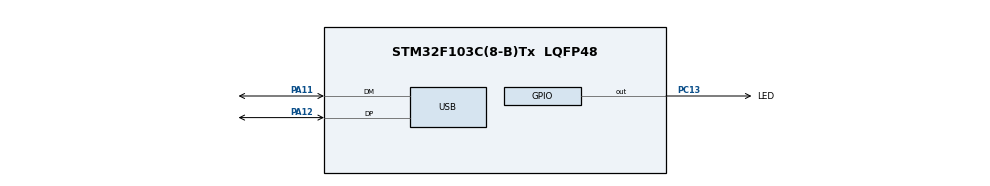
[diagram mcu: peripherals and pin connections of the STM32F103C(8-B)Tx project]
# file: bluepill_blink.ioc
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Mcu.Family=STM32F1
Mcu.Name=STM32F103C(8-B)Tx
Mcu.Package=LQFP48
NVIC.PriorityGroup=NVIC_PRIORITYGROUP_4
NVIC.USB_LP_CAN1_RX0_IRQn=true\:0\:0\:false\:false\:true
PA11.Mode=Device
PA11.Signal=USB_DM
PA12.Mode=Device
PA12.Signal=USB_DP
PA13.Mode=Serial_Wire
PA13.Signal=SYS_JTMS-SWDIO
PA14.Mode=Serial_Wire
PA14.Signal=SYS_JTCK-SWCLK
PC13-TAMPER-RTC.GPIO_Label=LED
PC13-TAMPER-RTC.Signal=GPIO_Output
PD0-OSC_IN.Mode=HSE-External-Oscillator
PD0-OSC_IN.Signal=RCC_OSC_IN
PD1-OSC_OUT.Mode=HSE-External-Oscillator
PD1-OSC_OUT.Signal=RCC_OSC_OUT
ProjectManager.HeapSize=0x200
ProjectManager.StackSize=0x400
ProjectManager.TargetToolchain=Makefile
RCC.AHBFreq_Value=48000000
RCC.APB1CLKDivider=RCC_HCLK_DIV2
RCC.APB1Freq_Value=24000000
RCC.APB1TimFreq_Value=48000000
RCC.APB2Freq_Value=48000000
RCC.APB2TimFreq_Value=48000000
RCC.HCLKFreq_Value=48000000
RCC.PLLMUL=RCC_PLL_MUL6
RCC.PLLSourceVirtual=RCC_PLLSOURCE_HSE
RCC.SYSCLKFreq_VALUE=48000000
RCC.SYSCLKSource=RCC_SYSCLKSOURCE_PLLCLK
RCC.USBFreq_Value=48000000
USB_DEVICE.CLASS_NAME_FS=CDC
USB_DEVICE.VirtualMode=Cdc
USB_DEVICE.VirtualModeFS=Cdc_FS
VP_USB_DEVICE_VS_USB_DEVICE_CDC_FS.Mode=CDC_FS
board=bluepill_blink

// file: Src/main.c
/**
  ******************************************************************************
  * File Name          : main.c
  * Description        : Main program body
  ******************************************************************************
  * This notice applies to any and all portions of this file
  * that are not between comment pairs USER CODE BEGIN and
  * USER CODE END. Other portions of this file, whether
  * inserted by the user or by software development tools
  * are owned by their respective copyright owners.
  *
  * Copyright (c) 2017 STMicroelectronics International N.V.
  * All rights reserved.
  *
  * Redistribution and use in source and binary forms, with or without
  * modification, are permitted, provided that the following conditions are met:
  *
  * 1. Redistribution of source code must retain the above copyright notice,
  *    this list of conditions and the following disclaimer.
  * 2. Redistributions in binary form must reproduce the above copyright notice,
  *    this list of conditions and the following disclaimer in the documentation
  *    and/or other materials provided with the distribution.
  * 3. Neither the name of STMicroelectronics nor the names of other
  *    contributors to this software may be used to endorse or promote products
  *    derived from this software without specific written permission.
  * 4. This software, including modifications and/or derivative works of this
  *    software, must execute solely and exclusively on microcontroller or
  *    microprocessor devices manufactured by or for STMicroelectronics.
  * 5. Redistribution and use of this software other than as permitted under
  *    this license is void and will automatically terminate your rights under
  *    this license.
  *
  * THIS SOFTWARE IS PROVIDED BY STMICROELECTRONICS AND CONTRIBUTORS "AS IS"
  * AND ANY EXPRESS, IMPLIED OR STATUTORY WARRANTIES, INCLUDING, BUT NOT
  * LIMITED TO, THE IMPLIED WARRANTIES OF MERCHANTABILITY, FITNESS FOR A
  * PARTICULAR PURPOSE AND NON-INFRINGEMENT OF THIRD PARTY INTELLECTUAL PROPERTY
  * RIGHTS ARE DISCLAIMED TO THE FULLEST EXTENT PERMITTED BY LAW. IN NO EVENT
  * SHALL STMICROELECTRONICS OR CONTRIBUTORS BE LIABLE FOR ANY DIRECT, INDIRECT,
  * INCIDENTAL, SPECIAL, EXEMPLARY, OR CONSEQUENTIAL DAMAGES (INCLUDING, BUT NOT
  * LIMITED TO, PROCUREMENT OF SUBSTITUTE GOODS OR SERVICES; LOSS OF USE, DATA,
  * OR PROFITS; OR BUSINESS INTERRUPTION) HOWEVER CAUSED AND ON ANY THEORY OF
  * LIABILITY, WHETHER IN CONTRACT, STRICT LIABILITY, OR TORT (INCLUDING
  * NEGLIGENCE OR OTHERWISE) ARISING IN ANY WAY OUT OF THE USE OF THIS SOFTWARE,
  * EVEN IF ADVISED OF THE POSSIBILITY OF SUCH DAMAGE.
  *
  ******************************************************************************
  */
#include "main.h"
#include "stm32f1xx_hal.h"
#include "usb_device.h"

/* USER CODE BEGIN Includes */
#include "stm32f1xx_hal_rtc_ex.h"
/* USER CODE END Includes */

RTC_HandleTypeDef hrtc;
char reboot=0;
/* USER CODE BEGIN PV */
/* Private variables ---------------------------------------------------------*/

/* USER CODE END PV */

void SystemClock_Config(void);
static void MX_GPIO_Init(void);

/* USER CODE BEGIN PFP */
/* Private function prototypes -----------------------------------------------*/

/* USER CODE END PFP */

/* USER CODE BEGIN 0 */
void usb_rx(uint8_t *buf,int len){
  if(len >= 8){
    //if(dtr_pin > 3)
    {
      if((buf[0] == '1')&&(buf[1] == 'E')&&(buf[2] == 'A')&&(buf[3] == 'F') &&
         (buf[4] == '1')&&(buf[5] == 'E')&&(buf[6] == 'A')&&(buf[7] == 'F')){
          reboot=1;
        }
        //dtr_pin = 0;
    }
  }
}

/* USER CODE END 0 */

int main(void)
{

  /* USER CODE BEGIN 1 */
  //NVIC_SetVectorTable(NVIC_VectTab_FLASH, 0x4000);

  /* USER CODE END 1 */

  /* MCU Configuration----------------------------------------------------------*/

  /* Reset of all peripherals, Initializes the Flash interface and the Systick. */
  HAL_Init();

  /* USER CODE BEGIN Init */
  //this is the offset of our vector table
  SCB->VTOR = (FLASH_BASE | 0x4000);

  /* USER CODE END Init */

  /* Configure the system clock */
  SystemClock_Config();

  /* USER CODE BEGIN SysInit */
  #if 1
  __HAL_RCC_GPIOA_CLK_ENABLE();

  GPIO_InitTypeDef GPIO_InitStruct;

  GPIO_InitStruct.Pin = GPIO_PIN_12;
  GPIO_InitStruct.Mode = GPIO_MODE_OUTPUT_PP;
  GPIO_InitStruct.Speed = GPIO_SPEED_FREQ_LOW;
  HAL_GPIO_Init(GPIOA, &GPIO_InitStruct);

  HAL_GPIO_WritePin(GPIOA,GPIO_PIN_12, 0);
  HAL_Delay(100);
  HAL_GPIO_DeInit(GPIOA,GPIO_PIN_12);

  __HAL_RCC_GPIOA_CLK_DISABLE();
#endif

  /* USER CODE END SysInit */

  /* Initialize all configured peripherals */
  MX_GPIO_Init();
  MX_USB_DEVICE_Init();

  /* Infinite loop */
  while (1)
  {

  /* USER CODE BEGIN 3 */
    if(reboot){
      for(int i=0;i<30;i++){
        HAL_GPIO_TogglePin(LED_GPIO_Port,LED_Pin);
        HAL_Delay(50);
      }

      hrtc.Instance = RTC;
      hrtc.Init.AsynchPrediv = RTC_AUTO_1_SECOND;
      hrtc.Init.OutPut = RTC_OUTPUTSOURCE_ALARM;
      HAL_RTC_Init(&hrtc);
      HAL_RTCEx_BKUPWrite(&hrtc,RTC_BKP_DR10,0xdeaf);
      HAL_RTC_DeInit(&hrtc);

      HAL_NVIC_SystemReset();

    }

    HAL_GPIO_TogglePin(LED_GPIO_Port,LED_Pin);
    HAL_Delay(1000);

  }
  /* USER CODE END 3 */

}

/** System Clock Configuration
*/
void SystemClock_Config(void)
{

  RCC_OscInitTypeDef RCC_OscInitStruct;
  RCC_ClkInitTypeDef RCC_ClkInitStruct;
  RCC_PeriphCLKInitTypeDef PeriphClkInit;

    /**Initializes the CPU, AHB and APB busses clocks
    */
  RCC_OscInitStruct.OscillatorType = RCC_OSCILLATORTYPE_LSI|RCC_OSCILLATORTYPE_HSE;
  RCC_OscInitStruct.HSEState = RCC_HSE_ON;
  RCC_OscInitStruct.HSEPredivValue = RCC_HSE_PREDIV_DIV1;
  RCC_OscInitStruct.HSIState = RCC_HSI_ON;
  RCC_OscInitStruct.LSIState = RCC_LSI_ON;
  RCC_OscInitStruct.PLL.PLLState = RCC_PLL_ON;
  RCC_OscInitStruct.PLL.PLLSource = RCC_PLLSOURCE_HSE;
  RCC_OscInitStruct.PLL.PLLMUL = RCC_PLL_MUL9;
  if (HAL_RCC_OscConfig(&RCC_OscInitStruct) != HAL_OK)
  {
    _Error_Handler(__FILE__, __LINE__);
  }

    /**Initializes the CPU, AHB and APB busses clocks
    */
  RCC_ClkInitStruct.ClockType = RCC_CLOCKTYPE_HCLK|RCC_CLOCKTYPE_SYSCLK
                              |RCC_CLOCKTYPE_PCLK1|RCC_CLOCKTYPE_PCLK2;
  RCC_ClkInitStruct.SYSCLKSource = RCC_SYSCLKSOURCE_PLLCLK;
  RCC_ClkInitStruct.AHBCLKDivider = RCC_SYSCLK_DIV1;
  RCC_ClkInitStruct.APB1CLKDivider = RCC_HCLK_DIV2;
  RCC_ClkInitStruct.APB2CLKDivider = RCC_HCLK_DIV1;

  if (HAL_RCC_ClockConfig(&RCC_ClkInitStruct, FLASH_LATENCY_2) != HAL_OK)
  {
    _Error_Handler(__FILE__, __LINE__);
  }

  PeriphClkInit.PeriphClockSelection = RCC_PERIPHCLK_RTC|RCC_PERIPHCLK_USB;
  PeriphClkInit.RTCClockSelection = RCC_RTCCLKSOURCE_LSI;
  PeriphClkInit.UsbClockSelection = RCC_USBCLKSOURCE_PLL_DIV1_5;
  if (HAL_RCCEx_PeriphCLKConfig(&PeriphClkInit) != HAL_OK)
  {
    _Error_Handler(__FILE__, __LINE__);
  }

    /**Configure the Systick interrupt time
    */
  HAL_SYSTICK_Config(HAL_RCC_GetHCLKFreq()/1000);

    /**Configure the Systick
    */
  HAL_SYSTICK_CLKSourceConfig(SYSTICK_CLKSOURCE_HCLK);

  /* SysTick_IRQn interrupt configuration */
  HAL_NVIC_SetPriority(SysTick_IRQn, 0, 0);
}

/** Configure pins as
        * Analog
        * Input
        * Output
        * EVENT_OUT
        * EXTI
*/
static void MX_GPIO_Init(void)
{

  GPIO_InitTypeDef GPIO_InitStruct;

  /* GPIO Ports Clock Enable */
  __HAL_RCC_GPIOC_CLK_ENABLE();
  __HAL_RCC_GPIOD_CLK_ENABLE();
  __HAL_RCC_GPIOA_CLK_ENABLE();

  /*Configure GPIO pin Output Level */
  HAL_GPIO_WritePin(LED_GPIO_Port, LED_Pin, GPIO_PIN_RESET);

  /*Configure GPIO pin : LED_Pin */
  GPIO_InitStruct.Pin = LED_Pin;
  GPIO_InitStruct.Mode = GPIO_MODE_OUTPUT_PP;
  GPIO_InitStruct.Speed = GPIO_SPEED_FREQ_LOW;
  HAL_GPIO_Init(LED_GPIO_Port, &GPIO_InitStruct);

}

void _Error_Handler(char * file, int line)
{
  while(1)
  {
  }
}

/************************ (C) COPYRIGHT STMicroelectronics *****END OF FILE****/
